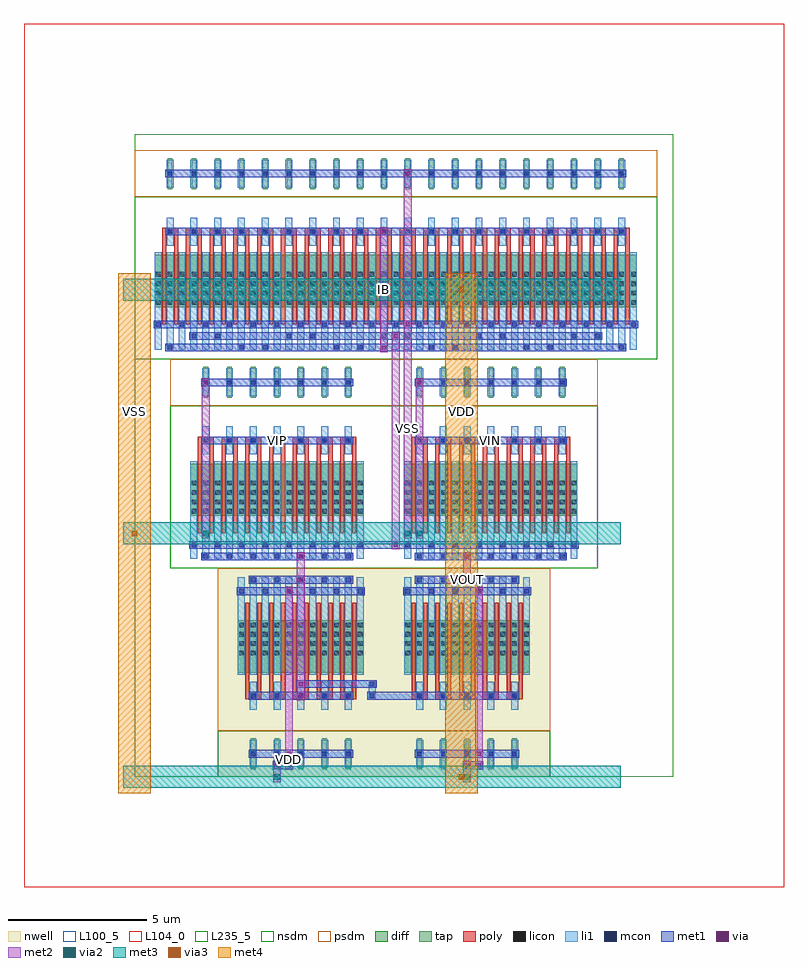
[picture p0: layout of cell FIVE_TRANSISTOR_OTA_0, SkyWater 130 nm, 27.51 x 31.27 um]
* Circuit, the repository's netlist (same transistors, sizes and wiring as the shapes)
* NGSPICE file created from FIVE_TRANSISTOR_OTA_0.ext - technology: sky130A

.subckt DCL_PMOS_S_9664157_X5_Y1_1774869020 a_200_252# w_0_0#
X0 a_200_252# a_200_252# w_0_0# w_0_0# sky130_fd_pr__pfet_01v8 ad=0.2646 pd=2.17 as=0.2646 ps=2.17 w=1.89 l=0.15 M=10
.ends

.subckt PMOS_S_72158034_X5_Y1_1774869022 a_200_252# a_230_378# w_0_0#
X0 a_230_378# a_200_252# w_0_0# w_0_0# sky130_fd_pr__pfet_01v8 ad=0.2646 pd=2.17 as=0.2646 ps=2.17 w=1.89 l=0.15 M=10
.ends

.subckt SCM_NMOS_26075846_X10_Y1_1774869023 a_200_252# a_402_378# a_147_378#
X0 a_147_378# a_200_252# a_402_378# a_147_378# sky130_fd_pr__nfet_01v8 ad=0.2646 pd=2.17 as=0.2646 ps=2.17 w=1.89 l=0.15 M=20
X1 a_147_378# a_200_252# a_200_252# a_147_378# sky130_fd_pr__nfet_01v8 ad=0.50085 pd=4.31 as=0.2646 ps=2.17 w=1.89 l=0.15 M=20
.ends

.subckt NMOS_4T_39571376_X7_Y1_1774869021 a_200_252# a_230_378# a_147_378# a_241_1232#
X0 a_230_378# a_200_252# a_147_378# a_241_1232# sky130_fd_pr__nfet_01v8 ad=0.2646 pd=2.17 as=0.2646 ps=2.17 w=1.89 l=0.15 M=14
.ends

.subckt FIVE_TRANSISTOR_OTA_0 IB VOUT VIP VIN VSS VDD
XDCL_PMOS_S_9664157_X5_Y1_1774869020_0 li_1695_571# VDD DCL_PMOS_S_9664157_X5_Y1_1774869020
XPMOS_S_72158034_X5_Y1_1774869022_0 li_1695_571# VOUT VDD PMOS_S_72158034_X5_Y1_1774869022
XSCM_NMOS_26075846_X10_Y1_1774869023_0 IB m1_1634_1652# VSS SCM_NMOS_26075846_X10_Y1_1774869023
XNMOS_4T_39571376_X7_Y1_1774869021_0 VIN VOUT m1_1634_1652# VSS NMOS_4T_39571376_X7_Y1_1774869021
XNMOS_4T_39571376_X7_Y1_1774869021_1 VIP li_1695_571# m1_1634_1652# VSS NMOS_4T_39571376_X7_Y1_1774869021
.ends

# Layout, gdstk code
from math import pi, radians
import gdstk
lib = gdstk.Library(unit=1e-6, precision=1e-09)
def R(c, l, rs):  # rectangles x0, y0, x1, y1
    for r in rs: c.add(gdstk.rectangle(r[:2], r[2:], *l))
def A(c, l, x, y, w, h, nx, ny, dx, dy):  # array of equal rectangles
    R(c, l, [(x+i*dx, y+j*dy, x+i*dx+w, y+j*dy+h) for i in range(nx) for j in range(ny)])
def P(c, l, *ps):  # polygons
    for p in ps: c.add(gdstk.Polygon(p, *l))
nwell = (64, 20)
diff = (65, 20)
tap = (65, 44)
poly = (66, 20)
licon = (66, 44)
li1 = (67, 20)
mcon = (67, 44)
met1 = (68, 20)
via = (68, 44)
met2 = (69, 20)
via2 = (69, 44)
met3 = (70, 20)
via3 = (70, 44)
met4 = (71, 20)
nsdm = (93, 44)
psdm = (94, 20)
L100_5 = (100, 5)
L104_0 = (104, 0)
L235_5 = (235, 5)

scm_nmos_26075846_x10_y1 = lib.new_cell('SCM_NMOS_26075846_X10_Y1_1774869023')
R(scm_nmos_26075846_x10_y1, diff, [(0.735,1.89,18.185,3.78)])
A(scm_nmos_26075846_x10_y1, tap, 1.205, 6.16, 0.17, 1.12, 20, 1, 0.86, 0)
A(scm_nmos_26075846_x10_y1, poly, 1, 1.26, 0.15, 3.36, 40, 1, 0.43, 0)
A(scm_nmos_26075846_x10_y1, poly, 1, 4.485, 0.58, 0.27, 20, 1, 0.86, 0)
A(scm_nmos_26075846_x10_y1, licon, 0.775, 1.97, 0.17, 0.17, 3, 4, 0.43, 0.34)
A(scm_nmos_26075846_x10_y1, licon, 1.635, 1.97, 0.17, 0.17, 3, 4, 0.43, 0.34)
A(scm_nmos_26075846_x10_y1, licon, 2.495, 1.97, 0.17, 0.17, 3, 4, 0.43, 0.34)
A(scm_nmos_26075846_x10_y1, licon, 3.355, 1.97, 0.17, 0.17, 3, 4, 0.43, 0.34)
A(scm_nmos_26075846_x10_y1, licon, 4.215, 1.97, 0.17, 0.17, 3, 4, 0.43, 0.34)
A(scm_nmos_26075846_x10_y1, licon, 5.075, 1.97, 0.17, 0.17, 3, 4, 0.43, 0.34)
A(scm_nmos_26075846_x10_y1, licon, 5.935, 1.97, 0.17, 0.17, 3, 4, 0.43, 0.34)
A(scm_nmos_26075846_x10_y1, licon, 6.795, 1.97, 0.17, 0.17, 3, 4, 0.43, 0.34)
A(scm_nmos_26075846_x10_y1, licon, 7.655, 1.97, 0.17, 0.17, 3, 4, 0.43, 0.34)
A(scm_nmos_26075846_x10_y1, licon, 8.515, 1.97, 0.17, 0.17, 3, 4, 0.43, 0.34)
A(scm_nmos_26075846_x10_y1, licon, 9.375, 1.97, 0.17, 0.17, 3, 4, 0.43, 0.34)
A(scm_nmos_26075846_x10_y1, licon, 10.235, 1.97, 0.17, 0.17, 3, 4, 0.43, 0.34)
A(scm_nmos_26075846_x10_y1, licon, 11.095, 1.97, 0.17, 0.17, 3, 4, 0.43, 0.34)
A(scm_nmos_26075846_x10_y1, licon, 11.955, 1.97, 0.17, 0.17, 3, 4, 0.43, 0.34)
A(scm_nmos_26075846_x10_y1, licon, 12.815, 1.97, 0.17, 0.17, 3, 4, 0.43, 0.34)
A(scm_nmos_26075846_x10_y1, licon, 13.675, 1.97, 0.17, 0.17, 3, 4, 0.43, 0.34)
A(scm_nmos_26075846_x10_y1, licon, 14.535, 1.97, 0.17, 0.17, 3, 4, 0.43, 0.34)
A(scm_nmos_26075846_x10_y1, licon, 15.395, 1.97, 0.17, 0.17, 3, 4, 0.43, 0.34)
A(scm_nmos_26075846_x10_y1, licon, 16.255, 1.97, 0.17, 0.17, 3, 4, 0.43, 0.34)
A(scm_nmos_26075846_x10_y1, licon, 17.115, 1.97, 0.17, 0.17, 3, 4, 0.43, 0.34)
A(scm_nmos_26075846_x10_y1, licon, 1.205, 4.535, 0.17, 0.17, 20, 2, 0.86, 2.1)
A(scm_nmos_26075846_x10_y1, li1, 0.735, 0.335, 0.25, 3.53, 41, 1, 0.43, 0)
A(scm_nmos_26075846_x10_y1, li1, 1.165, 4.115, 0.25, 1.01, 20, 2, 0.86, 2.1)
A(scm_nmos_26075846_x10_y1, mcon, 0.775, 1.175, 0.17, 0.17, 21, 1, 0.86, 0)
A(scm_nmos_26075846_x10_y1, mcon, 1.205, 4.535, 0.17, 0.17, 20, 2, 0.86, 2.1)
R(scm_nmos_26075846_x10_y1, mcon, [(1.205,0.335,1.375,0.505), (3.785,0.335,3.955,0.505), (4.645,0.335,4.815,0.505), (7.225,0.335,7.395,0.505), (8.085,0.335,8.255,0.505), (10.665,0.335,10.835,0.505), (11.525,0.335,11.695,0.505), (14.105,0.335,14.275,0.505), (14.965,0.335,15.135,0.505), (17.545,0.335,17.715,0.505), (2.065,0.755,2.235,0.925), (2.925,0.755,3.095,0.925), (5.505,0.755,5.675,0.925), (6.365,0.755,6.535,0.925), (8.945,0.755,9.115,0.925), (9.805,0.755,9.975,0.925), (12.385,0.755,12.555,0.925), (13.245,0.755,13.415,0.925), (15.825,0.755,15.995,0.925), (16.685,0.755,16.855,0.925)])
R(scm_nmos_26075846_x10_y1, met1, [(1.12,0.28,17.8,0.56), (1.98,0.7,16.94,0.98), (0.69,1.12,18.23,1.4), (1.12,4.48,17.8,4.76), (1.12,6.58,17.8,6.86)])
R(scm_nmos_26075846_x10_y1, via, [(8.955,0.345,9.105,0.495), (9.815,1.185,9.965,1.335), (8.955,4.545,9.105,4.695), (9.815,6.645,9.965,6.795)])
R(scm_nmos_26075846_x10_y1, met2, [(8.89,0.26,9.17,4.78), (9.75,1.1,10.03,6.88)])
R(scm_nmos_26075846_x10_y1, nsdm, [(0,0,18.92,5.88)])
R(scm_nmos_26075846_x10_y1, psdm, [(0,5.88,18.92,7.56)])
R(scm_nmos_26075846_x10_y1, L100_5, [(0,0,18.92,7.56)])

dcl_pmos_s_9664157_x5_y1 = lib.new_cell('DCL_PMOS_S_9664157_X5_Y1_1774869020')
R(dcl_pmos_s_9664157_x5_y1, nwell, [(0,0,6.02,7.56)])
R(dcl_pmos_s_9664157_x5_y1, diff, [(0.735,1.89,5.285,3.78)])
A(dcl_pmos_s_9664157_x5_y1, tap, 1.205, 6.16, 0.17, 1.12, 5, 1, 0.86, 0)
A(dcl_pmos_s_9664157_x5_y1, poly, 1, 1.26, 0.15, 3.36, 10, 1, 0.43, 0)
A(dcl_pmos_s_9664157_x5_y1, poly, 1, 4.485, 0.58, 0.27, 5, 1, 0.86, 0)
A(dcl_pmos_s_9664157_x5_y1, licon, 0.775, 1.97, 0.17, 0.17, 3, 4, 0.43, 0.34)
A(dcl_pmos_s_9664157_x5_y1, licon, 1.635, 1.97, 0.17, 0.17, 3, 4, 0.43, 0.34)
A(dcl_pmos_s_9664157_x5_y1, licon, 2.495, 1.97, 0.17, 0.17, 3, 4, 0.43, 0.34)
A(dcl_pmos_s_9664157_x5_y1, licon, 3.355, 1.97, 0.17, 0.17, 3, 4, 0.43, 0.34)
A(dcl_pmos_s_9664157_x5_y1, licon, 4.215, 1.97, 0.17, 0.17, 3, 4, 0.43, 0.34)
A(dcl_pmos_s_9664157_x5_y1, licon, 1.205, 4.535, 0.17, 0.17, 5, 2, 0.86, 2.1)
A(dcl_pmos_s_9664157_x5_y1, li1, 0.735, 0.335, 0.25, 3.53, 11, 1, 0.43, 0)
A(dcl_pmos_s_9664157_x5_y1, li1, 1.165, 4.115, 0.25, 1.01, 5, 2, 0.86, 2.1)
A(dcl_pmos_s_9664157_x5_y1, mcon, 1.205, 0.335, 0.17, 0.17, 5, 2, 0.86, 4.2)
A(dcl_pmos_s_9664157_x5_y1, mcon, 0.775, 0.755, 0.17, 0.17, 6, 1, 0.86, 0)
A(dcl_pmos_s_9664157_x5_y1, mcon, 1.205, 6.635, 0.17, 0.17, 5, 1, 0.86, 0)
R(dcl_pmos_s_9664157_x5_y1, met1, [(1.12,0.28,4.9,0.56), (0.69,0.7,5.33,0.98), (1.12,4.48,4.9,4.76), (1.12,6.58,4.9,6.86)])
R(dcl_pmos_s_9664157_x5_y1, via, [(2.935,0.345,3.085,0.495), (3.365,0.765,3.515,0.915), (2.935,4.545,3.085,4.695), (3.365,6.645,3.515,6.795)])
R(dcl_pmos_s_9664157_x5_y1, met2, [(2.87,0.26,3.15,4.78), (3.3,0.68,3.58,6.88)])
R(dcl_pmos_s_9664157_x5_y1, nsdm, [(0,5.88,6.02,7.56)])
R(dcl_pmos_s_9664157_x5_y1, psdm, [(0,0,6.02,5.88)])
R(dcl_pmos_s_9664157_x5_y1, L100_5, [(0,0,6.02,7.56)])

pmos_s_72158034_x5_y1_17 = lib.new_cell('PMOS_S_72158034_X5_Y1_1774869022')
R(pmos_s_72158034_x5_y1_17, nwell, [(0,0,6.02,7.56)])
R(pmos_s_72158034_x5_y1_17, diff, [(0.735,1.89,5.285,3.78)])
A(pmos_s_72158034_x5_y1_17, tap, 1.205, 6.16, 0.17, 1.12, 5, 1, 0.86, 0)
A(pmos_s_72158034_x5_y1_17, poly, 1, 1.26, 0.15, 3.36, 10, 1, 0.43, 0)
A(pmos_s_72158034_x5_y1_17, poly, 1, 4.485, 0.58, 0.27, 5, 1, 0.86, 0)
A(pmos_s_72158034_x5_y1_17, licon, 0.775, 1.97, 0.17, 0.17, 3, 4, 0.43, 0.34)
A(pmos_s_72158034_x5_y1_17, licon, 1.635, 1.97, 0.17, 0.17, 3, 4, 0.43, 0.34)
A(pmos_s_72158034_x5_y1_17, licon, 2.495, 1.97, 0.17, 0.17, 3, 4, 0.43, 0.34)
A(pmos_s_72158034_x5_y1_17, licon, 3.355, 1.97, 0.17, 0.17, 3, 4, 0.43, 0.34)
A(pmos_s_72158034_x5_y1_17, licon, 4.215, 1.97, 0.17, 0.17, 3, 4, 0.43, 0.34)
A(pmos_s_72158034_x5_y1_17, licon, 1.205, 4.535, 0.17, 0.17, 5, 2, 0.86, 2.1)
A(pmos_s_72158034_x5_y1_17, li1, 0.735, 0.335, 0.25, 3.53, 11, 1, 0.43, 0)
A(pmos_s_72158034_x5_y1_17, li1, 1.165, 4.115, 0.25, 1.01, 5, 2, 0.86, 2.1)
A(pmos_s_72158034_x5_y1_17, mcon, 1.205, 0.335, 0.17, 0.17, 5, 2, 0.86, 4.2)
A(pmos_s_72158034_x5_y1_17, mcon, 0.775, 0.755, 0.17, 0.17, 6, 1, 0.86, 0)
A(pmos_s_72158034_x5_y1_17, mcon, 1.205, 6.635, 0.17, 0.17, 5, 1, 0.86, 0)
R(pmos_s_72158034_x5_y1_17, met1, [(1.12,0.28,4.9,0.56), (0.69,0.7,5.33,0.98), (1.12,4.48,4.9,4.76), (1.12,6.58,4.9,6.86)])
R(pmos_s_72158034_x5_y1_17, via, [(3.365,0.765,3.515,0.915), (3.365,6.645,3.515,6.795)])
R(pmos_s_72158034_x5_y1_17, met2, [(3.3,0.68,3.58,6.88)])
R(pmos_s_72158034_x5_y1_17, nsdm, [(0,5.88,6.02,7.56)])
R(pmos_s_72158034_x5_y1_17, psdm, [(0,0,6.02,5.88)])
R(pmos_s_72158034_x5_y1_17, L100_5, [(0,0,6.02,7.56)])

nmos_4t_39571376_x7_y1_1 = lib.new_cell('NMOS_4T_39571376_X7_Y1_1774869021')
R(nmos_4t_39571376_x7_y1_1, diff, [(0.735,1.89,7.005,3.78)])
A(nmos_4t_39571376_x7_y1_1, tap, 1.205, 6.16, 0.17, 1.12, 7, 1, 0.86, 0)
A(nmos_4t_39571376_x7_y1_1, poly, 1, 1.26, 0.15, 3.36, 14, 1, 0.43, 0)
A(nmos_4t_39571376_x7_y1_1, poly, 1, 4.485, 0.58, 0.27, 7, 1, 0.86, 0)
A(nmos_4t_39571376_x7_y1_1, licon, 0.775, 1.97, 0.17, 0.17, 3, 4, 0.43, 0.34)
A(nmos_4t_39571376_x7_y1_1, licon, 1.635, 1.97, 0.17, 0.17, 3, 4, 0.43, 0.34)
A(nmos_4t_39571376_x7_y1_1, licon, 2.495, 1.97, 0.17, 0.17, 3, 4, 0.43, 0.34)
A(nmos_4t_39571376_x7_y1_1, licon, 3.355, 1.97, 0.17, 0.17, 3, 4, 0.43, 0.34)
A(nmos_4t_39571376_x7_y1_1, licon, 4.215, 1.97, 0.17, 0.17, 3, 4, 0.43, 0.34)
A(nmos_4t_39571376_x7_y1_1, licon, 5.075, 1.97, 0.17, 0.17, 3, 4, 0.43, 0.34)
A(nmos_4t_39571376_x7_y1_1, licon, 5.935, 1.97, 0.17, 0.17, 3, 4, 0.43, 0.34)
A(nmos_4t_39571376_x7_y1_1, licon, 1.205, 4.535, 0.17, 0.17, 7, 2, 0.86, 2.1)
A(nmos_4t_39571376_x7_y1_1, li1, 0.735, 0.335, 0.25, 3.53, 15, 1, 0.43, 0)
A(nmos_4t_39571376_x7_y1_1, li1, 1.165, 4.115, 0.25, 1.01, 7, 2, 0.86, 2.1)
A(nmos_4t_39571376_x7_y1_1, mcon, 1.205, 0.335, 0.17, 0.17, 7, 2, 0.86, 4.2)
A(nmos_4t_39571376_x7_y1_1, mcon, 0.775, 0.755, 0.17, 0.17, 8, 1, 0.86, 0)
A(nmos_4t_39571376_x7_y1_1, mcon, 1.205, 6.635, 0.17, 0.17, 7, 1, 0.86, 0)
R(nmos_4t_39571376_x7_y1_1, met1, [(1.12,0.28,6.62,0.56), (0.69,0.7,7.05,0.98), (1.12,4.48,6.62,4.76), (1.12,6.58,6.62,6.86)])
R(nmos_4t_39571376_x7_y1_1, nsdm, [(0,0,7.74,5.88)])
R(nmos_4t_39571376_x7_y1_1, psdm, [(0,5.88,7.74,7.56)])
R(nmos_4t_39571376_x7_y1_1, L100_5, [(0,0,7.74,7.56)])

five_transistor_ota_0 = lib.new_cell('FIVE_TRANSISTOR_OTA_0')
R(five_transistor_ota_0, li1, [(8.475,2.855,8.725,3.025), (8.475,2.855,8.725,3.025), (8.475,2.94,8.725,3.36), (8.475,3.275,8.725,3.445), (8.475,3.275,8.725,3.445)])
R(five_transistor_ota_0, mcon, [(8.515,2.855,8.685,3.025), (8.515,2.855,8.685,3.025), (8.515,3.275,8.685,3.445), (8.515,3.275,8.685,3.445)])
R(five_transistor_ota_0, met1, [(5,0.28,5.32,0.56), (5,0.28,5.32,0.56), (5,0.28,5.32,0.56), (5.16,0.28,5.59,0.56), (5.43,0.28,5.75,0.56), (5.43,0.28,5.75,0.56), (5.43,0.28,5.75,0.56), (11.88,0.28,12.2,0.56), (11.88,0.28,12.2,0.56), (12.04,0.28,12.47,0.56), (12.31,0.28,12.63,0.56), (12.31,0.28,12.63,0.56), (8.43,2.8,8.77,3.08), (8.43,2.8,8.77,3.08), (8.6,2.8,10.32,3.08), (5.86,3.22,6.18,3.5), (5.86,3.22,6.18,3.5), (6.02,3.22,8.6,3.5), (8.43,3.22,8.77,3.5), (8.43,3.22,8.77,3.5), (11.88,7,12.2,7.28), (11.88,7,12.2,7.28), (5.86,7.84,6.18,8.12), (5.86,7.84,6.18,8.12), (5.86,7.84,6.18,8.12), (5.86,7.84,6.18,8.12), (11.88,7.84,12.2,8.12), (11.88,7.84,12.2,8.12), (8.17,8.26,9.89,8.54), (9.3,8.26,9.62,8.54), (9.3,8.26,9.62,8.54), (2.42,14.14,2.74,14.42), (2.42,14.14,2.74,14.42), (2.42,14.14,2.74,14.42), (10.16,14.14,10.48,14.42), (10.16,14.14,10.48,14.42), (9.3,15.82,9.62,16.1), (9.3,15.82,9.62,16.1)])
P(five_transistor_ota_0, met1, [(0,0),(0,0),(0,0),(0,0)],
  [(0,0),(0,0),(0,0),(0,0)],
  [(0,0),(0,0),(0,0),(0,0)],
  [(0,0),(0,0),(0,0),(0,0)],
  [(0,0),(0,0),(0,0),(0,0)],
  [(0,0),(0,0),(0,0),(0,0)],
  [(0,0),(0,0),(0,0),(0,0)],
  [(0,0),(0,0),(0,0),(0,0)],
  [(0,0),(0,0),(0,0),(0,0)],
  [(0,0),(0,0),(0,0),(0,0)],
  [(0,0),(0,0),(0,0),(0,0)],
  [(0,0),(0,0),(0,0),(0,0)],
  [(0,0),(0,0),(0,0),(0,0)],
  [(0,0),(0,0),(0,0),(0,0)])
R(five_transistor_ota_0, via, [(5.085,0.345,5.235,0.495), (5.085,0.345,5.235,0.495), (5.085,0.345,5.235,0.495), (5.515,0.345,5.665,0.495), (5.515,0.345,5.665,0.495), (5.515,0.345,5.665,0.495), (11.965,0.345,12.115,0.495), (11.965,0.345,12.115,0.495), (12.395,0.345,12.545,0.495), (12.395,0.345,12.545,0.495), (5.945,3.285,6.095,3.435), (5.945,3.285,6.095,3.435), (11.965,7.065,12.115,7.215), (11.965,7.065,12.115,7.215), (5.945,7.905,6.095,8.055), (5.945,7.905,6.095,8.055), (5.945,7.905,6.095,8.055), (5.945,7.905,6.095,8.055), (11.965,7.905,12.115,8.055), (11.965,7.905,12.115,8.055), (9.385,8.325,9.535,8.475), (9.385,8.325,9.535,8.475), (2.505,14.205,2.655,14.355), (2.505,14.205,2.655,14.355), (2.505,14.205,2.655,14.355), (10.245,14.205,10.395,14.355), (10.245,14.205,10.395,14.355), (9.385,15.885,9.535,16.035), (9.385,15.885,9.535,16.035)])
R(five_transistor_ota_0, met2, [(5.02,-0.185,5.3,0.185), (5.02,-0.185,5.3,0.185), (5.02,-0.185,5.3,0.185), (11.9,-0.185,12.18,0.185), (11.9,-0.185,12.18,0.185), (5.02,0,5.3,0.42), (11.9,0,12.18,0.42), (5.02,0.26,5.3,0.58), (5.02,0.26,5.3,0.58), (5.02,0.26,5.3,0.58), (5.45,0.26,5.73,0.58), (5.45,0.26,5.73,0.58), (5.45,0.26,5.73,0.58), (11.9,0.26,12.18,0.58), (11.9,0.26,12.18,0.58), (12.33,0.26,12.61,0.58), (12.33,0.26,12.61,0.58), (5.45,0.42,5.73,0.84), (12.33,0.42,12.61,0.84), (5.88,3.2,6.16,3.52), (5.88,3.2,6.16,3.52), (11.9,6.98,12.18,7.3), (11.9,6.98,12.18,7.3), (5.88,7.14,6.16,7.98), (11.9,7.14,12.18,7.98), (5.88,7.82,6.16,8.14), (5.88,7.82,6.16,8.14), (5.88,7.82,6.16,8.14), (5.88,7.82,6.16,8.14), (11.9,7.82,12.18,8.14), (11.9,7.82,12.18,8.14), (9.32,8.24,9.6,8.56), (9.32,8.24,9.6,8.56), (9.32,8.4,9.6,15.96), (2.44,8.635,2.72,9.005), (2.44,8.635,2.72,9.005), (2.44,8.635,2.72,9.005), (9.75,8.635,10.03,9.005), (9.75,8.635,10.03,9.005), (9.75,8.635,10.03,9.005), (9.75,8.635,10.03,9.005), (10.18,8.635,10.46,9.005), (10.18,8.635,10.46,9.005), (2.44,8.82,2.72,14.28), (9.75,8.82,10.03,16.38), (10.18,8.82,10.46,14.28), (2.44,14.12,2.72,14.44), (2.44,14.12,2.72,14.44), (2.44,14.12,2.72,14.44), (10.18,14.12,10.46,14.44), (10.18,14.12,10.46,14.44), (9.32,15.8,9.6,16.12), (9.32,15.8,9.6,16.12)])
P(five_transistor_ota_0, met2, [(0,0),(0,0),(0,0),(0,0)],
  [(0,0),(0,0),(0,0),(0,0)],
  [(0,0),(0,0),(0,0),(0,0)],
  [(0,0),(0,0),(0,0),(0,0)],
  [(0,0),(0,0),(0,0),(0,0)],
  [(0,0),(0,0),(0,0),(0,0)])
R(five_transistor_ota_0, via2, [(5.06,-0.1,5.26,0.1), (5.06,-0.1,5.26,0.1), (5.06,-0.1,5.26,0.1), (11.94,-0.1,12.14,0.1), (11.94,-0.1,12.14,0.1), (2.48,8.72,2.68,8.92), (2.48,8.72,2.68,8.92), (2.48,8.72,2.68,8.92), (9.79,8.72,9.99,8.92), (9.79,8.72,9.99,8.92), (9.79,8.72,9.99,8.92), (9.79,8.72,9.99,8.92), (10.22,8.72,10.42,8.92), (10.22,8.72,10.42,8.92)])
A(five_transistor_ota_0, met3, -0.4, -0.4, 4.24, 0.8, 3, 3, 3.44, 8.82)
A(five_transistor_ota_0, met3, 9.92, -0.4, 2.32, 0.8, 1, 3, 0, 8.82)
A(five_transistor_ota_0, met3, 11.44, -0.4, 2.72, 0.8, 1, 3, 0, 8.82)
A(five_transistor_ota_0, met3, 13.36, -0.4, 4.24, 0.8, 1, 3, 0, 8.82)
R(five_transistor_ota_0, met3, [(4.995,-0.4,5.325,0.4), (4.995,-0.4,5.325,0.4), (4.995,-0.4,5.325,0.4), (11.675,-0.4,12.005,0.4), (11.875,-0.4,12.205,0.4), (11.875,-0.4,12.205,0.4), (-0.165,8.42,0.165,9.22), (2.415,8.42,2.745,9.22), (2.415,8.42,2.745,9.22), (2.415,8.42,2.745,9.22), (9.725,8.42,10.055,9.22), (9.725,8.42,10.055,9.22), (9.725,8.42,10.055,9.22), (9.725,8.42,10.055,9.22), (10.155,8.42,10.485,9.22), (10.155,8.42,10.485,9.22), (11.675,17.24,12.005,18.04)])
R(five_transistor_ota_0, via3, [(11.74,-0.1,11.94,0.1), (-0.1,8.72,0.1,8.92), (11.74,17.54,11.94,17.74)])
R(five_transistor_ota_0, met4, [(-0.59,-0.59,0.59,9.41), (11.25,-0.59,12.43,9.41), (11.25,-0.165,12.43,0.165), (-0.59,8.23,0.59,18.23), (11.25,8.23,12.43,18.23), (-0.59,8.655,0.59,8.985), (11.25,17.475,12.43,17.805)])
R(five_transistor_ota_0, L104_0, [(-4,-4,23.51,27.27)])
R(five_transistor_ota_0, L235_5, [(0,0,19.51,23.27)])
five_transistor_ota_0.add(gdstk.Reference(scm_nmos_26075846_x10_y1, (0,15.12)))
five_transistor_ota_0.add(gdstk.Reference(dcl_pmos_s_9664157_x5_y1, (9.03,7.56), rotation=pi))
five_transistor_ota_0.add(gdstk.Reference(pmos_s_72158034_x5_y1_17, (9.03,7.56), x_reflection=True))
five_transistor_ota_0.add(gdstk.Reference(nmos_4t_39571376_x7_y1_1, (1.29,7.56)))
five_transistor_ota_0.add(gdstk.Reference(nmos_4t_39571376_x7_y1_1, (16.77,7.56), rotation=pi, x_reflection=True))
five_transistor_ota_0.add(gdstk.Label('IB', (9.03,17.64), layer=69, texttype=5))
five_transistor_ota_0.add(gdstk.Label('VOUT', (12.04,7.14), layer=68, texttype=5))
five_transistor_ota_0.add(gdstk.Label('VIP', (5.16,12.18), layer=68, texttype=5))
five_transistor_ota_0.add(gdstk.Label('VIN', (12.9,12.18), layer=68, texttype=5))
five_transistor_ota_0.add(gdstk.Label('VSS', (9.89,12.6), layer=69, texttype=5))
five_transistor_ota_0.add(gdstk.Label('VSS', (0,13.23), layer=71, texttype=5))
five_transistor_ota_0.add(gdstk.Label('VSS', (0,13.23), layer=71, texttype=5))
five_transistor_ota_0.add(gdstk.Label('VSS', (0,13.23), layer=71, texttype=5))
five_transistor_ota_0.add(gdstk.Label('VSS', (0,13.23), layer=71, texttype=5))
five_transistor_ota_0.add(gdstk.Label('VSS', (0,13.23), layer=71, texttype=5))
five_transistor_ota_0.add(gdstk.Label('VSS', (0,13.23), layer=71, texttype=5))
five_transistor_ota_0.add(gdstk.Label('VSS', (0,13.23), layer=71, texttype=5))
five_transistor_ota_0.add(gdstk.Label('VSS', (0,13.23), layer=71, texttype=5))
five_transistor_ota_0.add(gdstk.Label('VDD', (5.59,0.63), layer=69, texttype=5))
five_transistor_ota_0.add(gdstk.Label('VDD', (11.84,13.23), layer=71, texttype=5))
five_transistor_ota_0.add(gdstk.Label('VDD', (11.84,13.23), layer=71, texttype=5))
five_transistor_ota_0.add(gdstk.Label('VDD', (11.84,13.23), layer=71, texttype=5))
five_transistor_ota_0.add(gdstk.Label('VDD', (11.84,13.23), layer=71, texttype=5))
five_transistor_ota_0.add(gdstk.Label('VDD', (11.84,13.23), layer=71, texttype=5))
five_transistor_ota_0.add(gdstk.Label('VDD', (11.84,13.23), layer=71, texttype=5))
five_transistor_ota_0.add(gdstk.Label('VDD', (11.84,13.23), layer=71, texttype=5))
five_transistor_ota_0.add(gdstk.Label('VDD', (11.84,13.23), layer=71, texttype=5))

lib.write_gds('FIVE_TRANSISTOR_OTA_0.gds')
